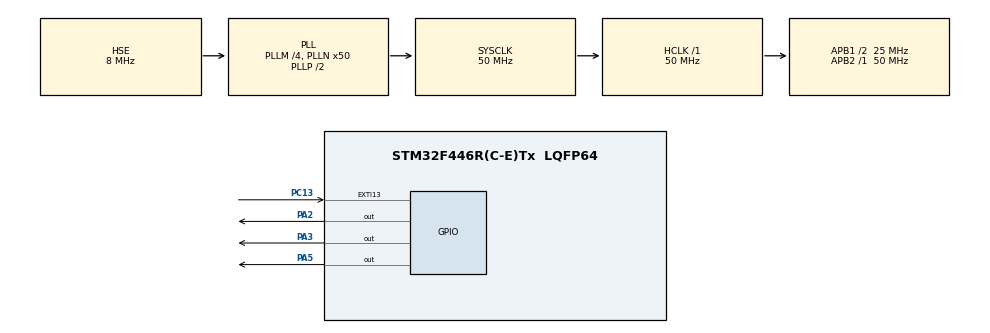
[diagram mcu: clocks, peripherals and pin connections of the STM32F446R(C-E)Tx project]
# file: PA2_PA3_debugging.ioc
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Mcu.Family=STM32F4
Mcu.Name=STM32F446R(C-E)Tx
Mcu.Package=LQFP64
NUCLEO-F446RE.BUTTON=1
NUCLEO-F446RE.LD1=true
NVIC.EXTI15_10_IRQn=true\:0\:0\:false\:false\:true\:false\:true\:true
NVIC.PriorityGroup=NVIC_PRIORITYGROUP_0
PA13.GPIO_Label=TMS
PA13.Signal=SYS_JTMS-SWDIO
PA14.GPIO_Label=TCK
PA14.Signal=SYS_JTCK-SWCLK
PA2.Signal=GPIO_Output
PA3.Signal=GPIO_Output
PA5.Signal=GPIO_Output
PB3.GPIO_Label=SWO
PB3.Signal=SYS_JTDO-SWO
PC13.Signal=GPXTI13
PC14-OSC32_IN.Signal=RCC_OSC32_IN
PC15-OSC32_OUT.Signal=RCC_OSC32_OUT
PH0-OSC_IN.Mode=HSE-External-Oscillator
PH0-OSC_IN.Signal=RCC_OSC_IN
PH1-OSC_OUT.Mode=HSE-External-Oscillator
PH1-OSC_OUT.Signal=RCC_OSC_OUT
ProjectManager.HeapSize=0x200
ProjectManager.StackSize=0x400
ProjectManager.TargetToolchain=STM32CubeIDE
RCC.AHBFreq_Value=50000000
RCC.APB1CLKDivider=RCC_HCLK_DIV2
RCC.APB1Freq_Value=25000000
RCC.APB1TimFreq_Value=50000000
RCC.APB2Freq_Value=50000000
RCC.APB2TimFreq_Value=50000000
RCC.CortexFreq_Value=50000000
RCC.FLatency-AdvancedSettings=FLASH_LATENCY_1
RCC.HCLKFreq_Value=50000000
RCC.HSE_VALUE=8000000
RCC.HSI_VALUE=16000000
RCC.LSE_VALUE=32768
RCC.PLLM=4
RCC.PLLN=50
RCC.PLLSourceVirtual=RCC_PLLSOURCE_HSE
RCC.SYSCLKFreq_VALUE=50000000
RCC.SYSCLKSource=RCC_SYSCLKSOURCE_PLLCLK
RCC.USBFreq_Value=50000000
RCC.VCOOutputFreq_Value=100000000
VP_NUCLEO-F446RE_VS_BSP_COMMON.Mode=COMMON
board=NUCLEO-F446RE

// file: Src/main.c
/* USER CODE BEGIN Header */
/**
  ******************************************************************************
  * @file           : main.c
  * @brief          : Main program body
  ******************************************************************************
  * @attention
  *
  * Copyright (c) 2026 STMicroelectronics.
  * All rights reserved.
  *
  * This software is licensed under terms that can be found in the LICENSE file
  * in the root directory of this software component.
  * If no LICENSE file comes with this software, it is provided AS-IS.
  *
  ******************************************************************************
  */
/* USER CODE END Header */
#include "main.h"

void SystemClock_Config(void);
static void MX_GPIO_Init(void);

int main(void)
{

  /* MCU Configuration--------------------------------------------------------*/

  /* Reset of all peripherals, Initializes the Flash interface and the Systick. */
  HAL_Init();

  /* Configure the system clock */
  SystemClock_Config();

  /* Initialize all configured peripherals */
  MX_GPIO_Init();

  /* Initialize leds */
  BSP_LED_Init(LED2);

  /* Initialize USER push-button, will be used to trigger an interrupt each time it's pressed.*/
  BSP_PB_Init(BUTTON_USER, BUTTON_MODE_EXTI);

  /* Infinite loop */
  /* USER CODE BEGIN WHILE */
  // HAL_GPIO_TogglePin(GPIOA, GPIO_PIN_2);
  //HAL_GPIO_WritePin(GPIOA, GPIO_PIN_2, 1);
  //HAL_GPIO_WritePin(GPIOA, GPIO_PIN_3, 1);

  while (1)
  {
	  BSP_LED_Toggle(LED2);
	  HAL_GPIO_TogglePin(GPIOA, GPIO_PIN_4);
	  HAL_GPIO_TogglePin(GPIOA, GPIO_PIN_6);
	  HAL_Delay(1000);
    /* USER CODE END WHILE */

  }
}

void SystemClock_Config(void)
{
  RCC_OscInitTypeDef RCC_OscInitStruct = {0};
  RCC_ClkInitTypeDef RCC_ClkInitStruct = {0};

  /** Configure the main internal regulator output voltage
  */
  __HAL_RCC_PWR_CLK_ENABLE();
  __HAL_PWR_VOLTAGESCALING_CONFIG(PWR_REGULATOR_VOLTAGE_SCALE3);

  /** Initializes the RCC Oscillators according to the specified parameters
  * in the RCC_OscInitTypeDef structure.
  */
  RCC_OscInitStruct.OscillatorType = RCC_OSCILLATORTYPE_HSE;
  RCC_OscInitStruct.HSEState = RCC_HSE_ON;
  RCC_OscInitStruct.PLL.PLLState = RCC_PLL_ON;
  RCC_OscInitStruct.PLL.PLLSource = RCC_PLLSOURCE_HSE;
  RCC_OscInitStruct.PLL.PLLM = 4;
  RCC_OscInitStruct.PLL.PLLN = 50;
  RCC_OscInitStruct.PLL.PLLP = RCC_PLLP_DIV2;
  RCC_OscInitStruct.PLL.PLLQ = 2;
  RCC_OscInitStruct.PLL.PLLR = 2;
  if (HAL_RCC_OscConfig(&RCC_OscInitStruct) != HAL_OK)
  {
    Error_Handler();
  }

  /** Initializes the CPU, AHB and APB buses clocks
  */
  RCC_ClkInitStruct.ClockType = RCC_CLOCKTYPE_HCLK|RCC_CLOCKTYPE_SYSCLK
                              |RCC_CLOCKTYPE_PCLK1|RCC_CLOCKTYPE_PCLK2;
  RCC_ClkInitStruct.SYSCLKSource = RCC_SYSCLKSOURCE_PLLCLK;
  RCC_ClkInitStruct.AHBCLKDivider = RCC_SYSCLK_DIV1;
  RCC_ClkInitStruct.APB1CLKDivider = RCC_HCLK_DIV2;
  RCC_ClkInitStruct.APB2CLKDivider = RCC_HCLK_DIV1;

  if (HAL_RCC_ClockConfig(&RCC_ClkInitStruct, FLASH_LATENCY_1) != HAL_OK)
  {
    Error_Handler();
  }
}

static void MX_GPIO_Init(void)
{
  GPIO_InitTypeDef GPIO_InitStruct = {0};

  /* GPIO Ports Clock Enable */
  __HAL_RCC_GPIOC_CLK_ENABLE();
  __HAL_RCC_GPIOH_CLK_ENABLE();
  __HAL_RCC_GPIOA_CLK_ENABLE();
  __HAL_RCC_GPIOB_CLK_ENABLE();

  /*Configure GPIO pin Output Level */
  HAL_GPIO_WritePin(GPIOA, GPIO_PIN_4|GPIO_PIN_6, GPIO_PIN_RESET);

  /*Configure GPIO pins : PA2 PA3 */
  GPIO_InitStruct.Pin = GPIO_PIN_4|GPIO_PIN_6;
  GPIO_InitStruct.Mode = GPIO_MODE_OUTPUT_PP;
  GPIO_InitStruct.Pull = GPIO_NOPULL;
  GPIO_InitStruct.Speed = GPIO_SPEED_FREQ_LOW;
  HAL_GPIO_Init(GPIOA, &GPIO_InitStruct);

}

void Error_Handler(void)
{
  __disable_irq();
  while (1)
  {
  }
}
